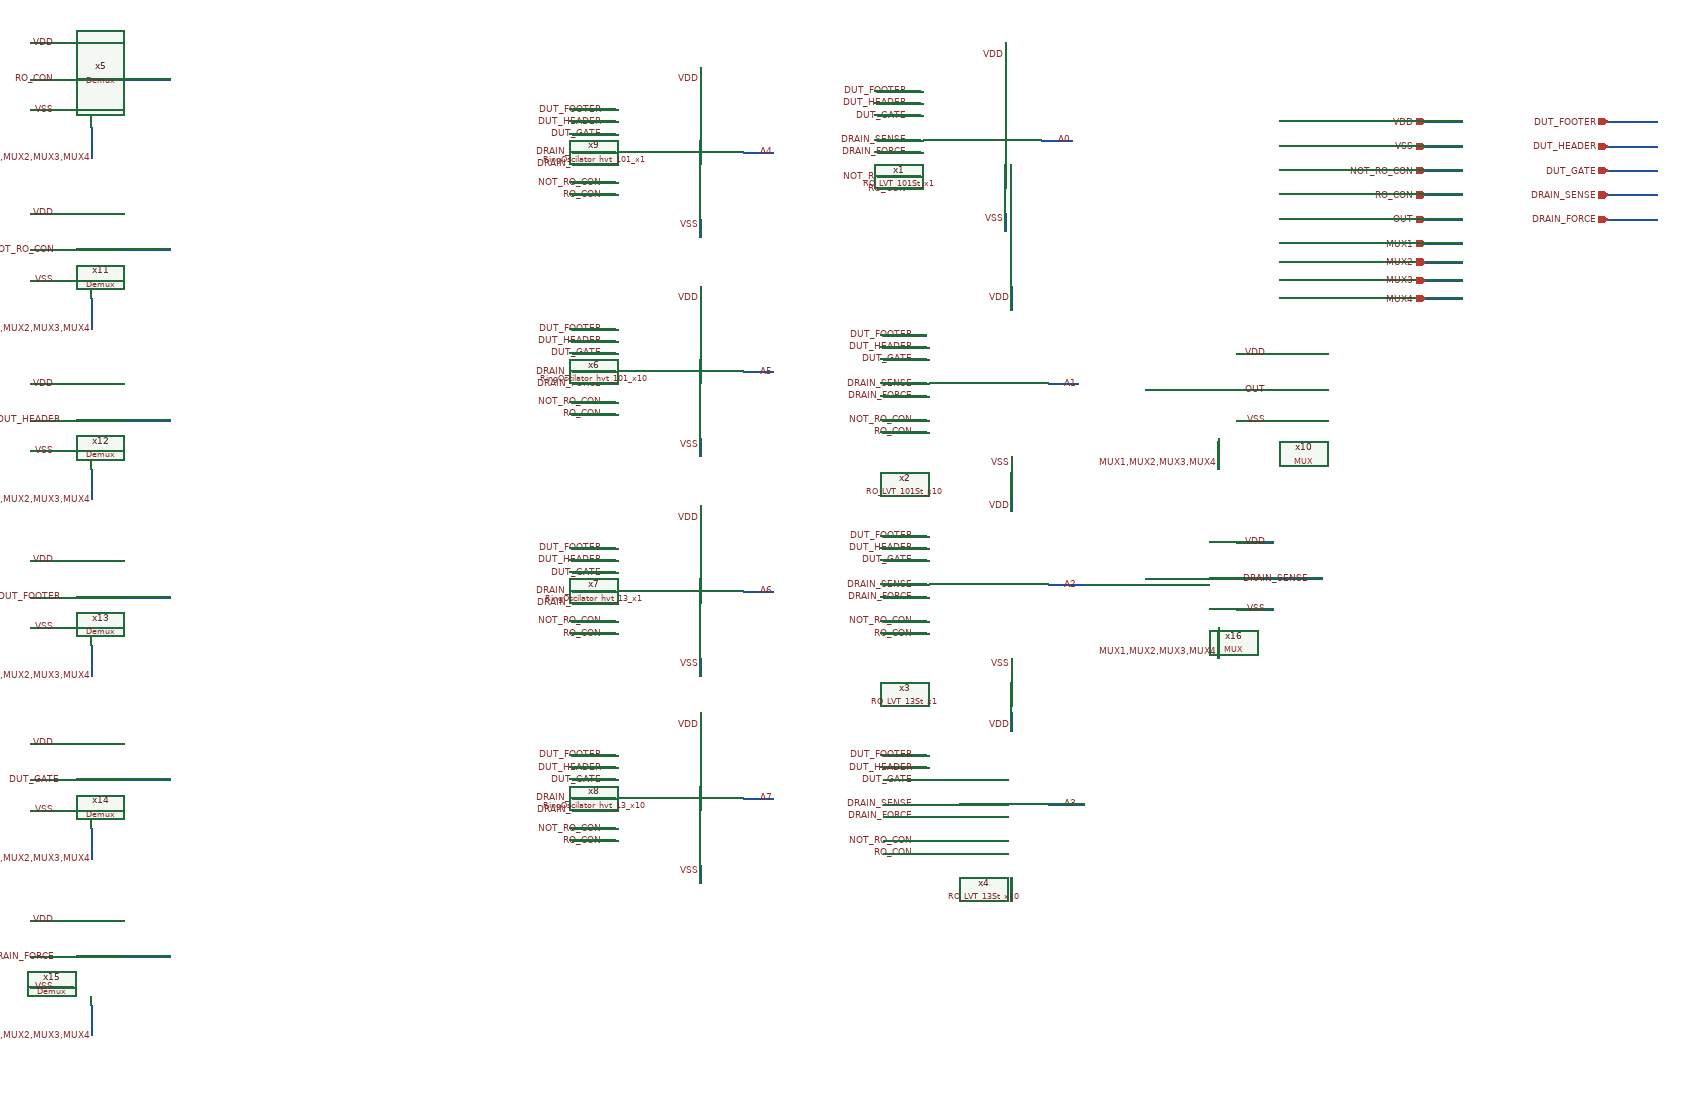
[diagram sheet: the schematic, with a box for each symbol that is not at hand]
v {xschem version=3.4.6RC file_version=1.2
}
G {}
K {}
V {}
S {}
E {}
N 210 -40 210 0 {
lab=VDD}
N 0 40 70 40 {
lab=DUT_FOOTER}
N 0 60 70 60 {
lab=DUT_HEADER}
N -0 80 70 80 {
lab=DUT_GATE}
N 0 120 70 120 {
lab=DRAIN_SENSE}
N 0 140 70 140 {
lab=DRAIN_FORCE}
N 0 180 70 180 {
lab=NOT_RO_CON}
N 0 200 70 200 {
lab=RO_CON}
N 270 120 320 120 {
lab=A1}
N 210 240 210 270 {
lab=VSS}
N 210 300 210 330 {
lab=VDD}
N 0 370 70 370 {
lab=DUT_FOOTER}
N 0 390 70 390 {
lab=DUT_HEADER}
N -0 410 70 410 {
lab=DUT_GATE}
N 0 450 70 450 {
lab=DRAIN_SENSE}
N -0 470 70 470 {
lab=DRAIN_FORCE}
N -0 510 70 510 {
lab=NOT_RO_CON}
N -0 530 70 530 {
lab=RO_CON}
N 210 570 210 610 {
lab=VSS}
N 270 450 330 450 {
lab=A2}
N 890 -310 950 -310 {
lab=VDD}
N 890 -270 950 -270 {
lab=VSS}
N 890 -230 950 -230 {
lab=NOT_RO_CON}
N 890 -190 950 -190 {
lab=RO_CON}
N 1190 -310 1270 -310 {
lab=DUT_FOOTER}
N 1190 -270 1270 -270 {
lab=DUT_HEADER}
N 1190 -230 1270 -230 {
lab=DUT_GATE}
N 1190 -190 1270 -190 {
lab=DRAIN_SENSE}
N 1190 -150 1270 -150 {
lab=DRAIN_FORCE}
N 890 -150 950 -150 {
lab=OUT}
N 890 -110 950 -110 {
lab=MUX1}
N 210 660 210 690 {
lab=VDD}
N 0 730 70 730 {
lab=DUT_FOOTER}
N 0 750 70 750 {
lab=DUT_HEADER}
N 0 770 70 770 {
lab=DUT_GATE}
N 0 810 70 810 {
lab=DRAIN_SENSE}
N 0 830 70 830 {
lab=DRAIN_FORCE}
N 0 870 70 870 {
lab=NOT_RO_CON}
N 0 890 70 890 {
lab=RO_CON}
N 210 930 210 970 {
lab=VSS}
N 270 810 330 810 {
lab=A3}
N 200 -440 200 -400 {
lab=VDD}
N -10 -360 60 -360 {
lab=DUT_FOOTER}
N -10 -340 60 -340 {
lab=DUT_HEADER}
N -10 -320 60 -320 {
lab=DUT_GATE}
N -10 -280 60 -280 {
lab=DRAIN_SENSE}
N -10 -260 60 -260 {
lab=DRAIN_FORCE}
N -10 -220 60 -220 {
lab=NOT_RO_CON}
N -10 -200 60 -200 {
lab=RO_CON}
N 260 -280 310 -280 {
lab=A0}
N 200 -160 200 -130 {
lab=VSS}
N -300 -400 -300 -360 {
lab=VDD}
N -510 -330 -440 -330 {
lab=DUT_FOOTER}
N -510 -310 -440 -310 {
lab=DUT_HEADER}
N -510 -290 -440 -290 {
lab=DUT_GATE}
N -510 -260 -440 -260 {
lab=DRAIN_SENSE}
N -510 -240 -440 -240 {
lab=DRAIN_FORCE}
N -510 -210 -440 -210 {
lab=NOT_RO_CON}
N -510 -190 -440 -190 {
lab=RO_CON}
N -230 -260 -180 -260 {
lab=A4}
N -300 -150 -300 -120 {
lab=VSS}
N -300 -40 -300 0 {
lab=VDD}
N -510 30 -440 30 {
lab=DUT_FOOTER}
N -510 50 -440 50 {
lab=DUT_HEADER}
N -510 70 -440 70 {
lab=DUT_GATE}
N -510 100 -440 100 {
lab=DRAIN_SENSE}
N -510 120 -440 120 {
lab=DRAIN_FORCE}
N -510 150 -440 150 {
lab=NOT_RO_CON}
N -510 170 -440 170 {
lab=RO_CON}
N -230 100 -180 100 {
lab=A5}
N -300 210 -300 240 {
lab=VSS}
N -300 320 -300 360 {
lab=VDD}
N -510 390 -440 390 {
lab=DUT_FOOTER}
N -510 410 -440 410 {
lab=DUT_HEADER}
N -510 430 -440 430 {
lab=DUT_GATE}
N -510 460 -440 460 {
lab=DRAIN_SENSE}
N -510 480 -440 480 {
lab=DRAIN_FORCE}
N -510 510 -440 510 {
lab=NOT_RO_CON}
N -510 530 -440 530 {
lab=RO_CON}
N -230 460 -180 460 {
lab=A6}
N -300 570 -300 600 {
lab=VSS}
N -300 660 -300 700 {
lab=VDD}
N -510 730 -440 730 {
lab=DUT_FOOTER}
N -510 750 -440 750 {
lab=DUT_HEADER}
N -510 770 -440 770 {
lab=DUT_GATE}
N -510 800 -440 800 {
lab=DRAIN_SENSE}
N -510 820 -440 820 {
lab=DRAIN_FORCE}
N -510 850 -440 850 {
lab=NOT_RO_CON}
N -510 870 -440 870 {
lab=RO_CON}
N -230 800 -180 800 {
lab=A7}
N -300 910 -300 940 {
lab=VSS}
N 580 70 640 70 {
lab=VDD}
N 580 130 640 130 {
lab=OUT}
N 580 180 640 180 {
lab=VSS}
N 550 210 550 260 {
lab=#net1}
N 430 130 510 130 {
lab=#net2}
N -1400 -380 -1330 -380 {
lab=RO_CON}
N -1400 -330 -1330 -330 {
lab=VSS}
N -1400 -440 -1330 -440 {
lab=VDD}
N -1300 -300 -1300 -250 {
lab=MUX1,MUX2,MUX3,MUX4}
N -1260 -380 -1170 -380 {
lab=#net3}
N -1400 -100 -1330 -100 {
lab=NOT_RO_CON}
N -1400 -50 -1330 -50 {
lab=VSS}
N -1400 -160 -1330 -160 {
lab=VDD}
N -1300 -20 -1300 30 {
lab=MUX1,MUX2,MUX3,MUX4}
N -1260 -100 -1170 -100 {
lab=#net4}
N -1400 180 -1330 180 {
lab=DUT_HEADER}
N -1400 230 -1330 230 {
lab=VSS}
N -1400 120 -1330 120 {
lab=VDD}
N -1300 260 -1300 310 {
lab=MUX1,MUX2,MUX3,MUX4}
N -1260 180 -1170 180 {
lab=#net5}
N -1400 470 -1330 470 {
lab=DUT_FOOTER}
N -1400 520 -1330 520 {
lab=VSS}
N -1400 410 -1330 410 {
lab=VDD}
N -1300 550 -1300 600 {
lab=MUX1,MUX2,MUX3,MUX4}
N -1260 470 -1170 470 {
lab=#net6}
N -1400 770 -1330 770 {
lab=DUT_GATE}
N -1400 820 -1330 820 {
lab=VSS}
N -1400 710 -1330 710 {
lab=VDD}
N -1300 850 -1300 900 {
lab=MUX1,MUX2,MUX3,MUX4}
N -1260 770 -1170 770 {
lab=#net7}
N -1400 1060 -1330 1060 {
lab=DRAIN_FORCE}
N -1400 1110 -1330 1110 {
lab=VSS}
N -1400 1000 -1330 1000 {
lab=VDD}
N -1300 1140 -1300 1190 {
lab=MUX1,MUX2,MUX3,MUX4}
N -1260 1060 -1170 1060 {
lab=#net8}
N 890 -80 950 -80 {
lab=MUX2}
N 890 -50 950 -50 {
lab=MUX3}
N 890 -20 950 -20 {
lab=MUX4}
N 580 380 640 380 {
lab=VDD}
N 580 440 640 440 {
lab=DRAIN_SENSE}
N 580 490 640 490 {
lab=VSS}
N 550 520 550 570 {
lab=#net9}
N 430 440 510 440 {
lab=#net10}
N 640 440 720 440 {
lab=DRAIN_SENSE}
C {lab_wire.sym} 210 -20 0 0 {name=p2 sig_type=std_logic lab=VDD}
C {lab_wire.sym} 210 320 0 0 {name=p3 sig_type=std_logic lab=VDD}
C {lab_wire.sym} 210 580 2 1 {name=p4 sig_type=std_logic lab=VSS}
C {lab_wire.sym} 210 250 2 1 {name=p5 sig_type=std_logic lab=VSS}
C {lab_wire.sym} 50 60 0 0 {name=p14 sig_type=std_logic lab=DUT_HEADER}
C {lab_wire.sym} 50 40 0 0 {name=p15 sig_type=std_logic lab=DUT_FOOTER}
C {lab_wire.sym} 50 80 0 0 {name=p16 sig_type=std_logic lab=DUT_GATE}
C {lab_wire.sym} 50 120 0 0 {name=p17 sig_type=std_logic lab=DRAIN_SENSE}
C {lab_wire.sym} 50 140 0 0 {name=p18 sig_type=std_logic lab=DRAIN_FORCE}
C {lab_wire.sym} 50 180 0 0 {name=p19 sig_type=std_logic lab=NOT_RO_CON}
C {lab_wire.sym} 50 200 0 0 {name=p20 sig_type=std_logic lab=RO_CON}
C {lab_wire.sym} 50 390 0 0 {name=p21 sig_type=std_logic lab=DUT_HEADER}
C {lab_wire.sym} 50 370 0 0 {name=p22 sig_type=std_logic lab=DUT_FOOTER}
C {lab_wire.sym} 50 410 0 0 {name=p23 sig_type=std_logic lab=DUT_GATE}
C {lab_wire.sym} 50 450 0 0 {name=p24 sig_type=std_logic lab=DRAIN_SENSE}
C {lab_wire.sym} 50 470 0 0 {name=p25 sig_type=std_logic lab=DRAIN_FORCE}
C {lab_wire.sym} 50 510 0 0 {name=p26 sig_type=std_logic lab=NOT_RO_CON}
C {lab_wire.sym} 50 530 0 0 {name=p27 sig_type=std_logic lab=RO_CON}
C {lab_wire.sym} 320 120 0 0 {name=p29 sig_type=std_logic lab=A1}
C {lab_wire.sym} 320 450 0 0 {name=p30 sig_type=std_logic lab=A2}
C {iopin.sym} 890 -310 2 0 {name=p81 lab=VDD}
C {iopin.sym} 890 -270 2 0 {name=p82 lab=VSS}
C {iopin.sym} 890 -230 2 0 {name=p83 lab=NOT_RO_CON}
C {iopin.sym} 890 -190 2 0 {name=p84 lab=RO_CON}
C {iopin.sym} 1190 -310 2 0 {name=p85 lab=DUT_FOOTER}
C {iopin.sym} 1190 -270 2 0 {name=p86 lab=DUT_HEADER}
C {iopin.sym} 1190 -230 2 0 {name=p87 lab=DUT_GATE}
C {iopin.sym} 1190 -190 2 0 {name=p88 lab=DRAIN_SENSE}
C {iopin.sym} 1190 -150 2 0 {name=p89 lab=DRAIN_FORCE}
C {iopin.sym} 890 -150 2 0 {name=p90 lab=OUT}
C {iopin.sym} 890 -110 2 0 {name=p37 lab=MUX1}
C {/foss/designs/RO_Aging_UNICASS/LVT/RO_LVT_101St_x10/RO_LVT_101St_x10.sym} 70 240 0 0 {name=x2}
C {/foss/designs/RO_Aging_UNICASS/LVT/RO_LVT_13St_x1/RO_LVT_13St_x1.sym} 50 570 0 0 {name=x3}
C {lab_wire.sym} 210 680 0 0 {name=p38 sig_type=std_logic lab=VDD}
C {lab_wire.sym} 210 940 2 1 {name=p39 sig_type=std_logic lab=VSS}
C {lab_wire.sym} 50 750 0 0 {name=p40 sig_type=std_logic lab=DUT_HEADER}
C {lab_wire.sym} 50 730 0 0 {name=p41 sig_type=std_logic lab=DUT_FOOTER}
C {lab_wire.sym} 50 770 0 0 {name=p42 sig_type=std_logic lab=DUT_GATE}
C {lab_wire.sym} 50 810 0 0 {name=p43 sig_type=std_logic lab=DRAIN_SENSE}
C {lab_wire.sym} 50 830 0 0 {name=p44 sig_type=std_logic lab=DRAIN_FORCE}
C {lab_wire.sym} 50 870 0 0 {name=p45 sig_type=std_logic lab=NOT_RO_CON}
C {lab_wire.sym} 50 890 0 0 {name=p46 sig_type=std_logic lab=RO_CON}
C {lab_wire.sym} 320 810 0 0 {name=p47 sig_type=std_logic lab=A3}
C {/foss/designs/RO_Aging_UNICASS/LVT/RO_LVT_13St_x10/RO_LVT_13St_x10.sym} 50 930 0 0 {name=x4}
C {lab_wire.sym} 200 -420 0 0 {name=p1 sig_type=std_logic lab=VDD}
C {lab_wire.sym} 200 -150 2 1 {name=p6 sig_type=std_logic lab=VSS}
C {lab_wire.sym} 40 -340 0 0 {name=p7 sig_type=std_logic lab=DUT_HEADER}
C {lab_wire.sym} 40 -360 0 0 {name=p8 sig_type=std_logic lab=DUT_FOOTER}
C {lab_wire.sym} 40 -320 0 0 {name=p9 sig_type=std_logic lab=DUT_GATE}
C {lab_wire.sym} 40 -280 0 0 {name=p10 sig_type=std_logic lab=DRAIN_SENSE}
C {lab_wire.sym} 40 -260 0 0 {name=p11 sig_type=std_logic lab=DRAIN_FORCE}
C {lab_wire.sym} 40 -220 0 0 {name=p12 sig_type=std_logic lab=NOT_RO_CON}
C {lab_wire.sym} 40 -200 0 0 {name=p13 sig_type=std_logic lab=RO_CON}
C {lab_wire.sym} 310 -280 0 0 {name=p48 sig_type=std_logic lab=A0}
C {/foss/designs/RO_Aging_UNICASS/LVT/RO_LVT_101St_x1/RO_LVT_101St_x1.sym} 60 -160 0 0 {name=x1}
C {lab_wire.sym} -300 -380 0 0 {name=p78 sig_type=std_logic lab=VDD}
C {lab_wire.sym} -300 -140 2 1 {name=p79 sig_type=std_logic lab=VSS}
C {lab_wire.sym} -460 -310 0 0 {name=p80 sig_type=std_logic lab=DUT_HEADER}
C {lab_wire.sym} -460 -330 0 0 {name=p91 sig_type=std_logic lab=DUT_FOOTER}
C {lab_wire.sym} -460 -290 0 0 {name=p92 sig_type=std_logic lab=DUT_GATE}
C {lab_wire.sym} -460 -260 0 0 {name=p93 sig_type=std_logic lab=DRAIN_SENSE}
C {lab_wire.sym} -460 -240 0 0 {name=p94 sig_type=std_logic lab=DRAIN_FORCE}
C {lab_wire.sym} -460 -210 0 0 {name=p95 sig_type=std_logic lab=NOT_RO_CON}
C {lab_wire.sym} -460 -190 0 0 {name=p96 sig_type=std_logic lab=RO_CON}
C {lab_wire.sym} -180 -260 0 0 {name=p97 sig_type=std_logic lab=A4}
C {/foss/designs/RO_Aging_UNICASS/HVT/RingOscilator_hvt_101_x1/RingOscilator_hvt_101_x1.sym} -330 -260 0 0 {name=x9}
C {lab_wire.sym} -300 -20 0 0 {name=p28 sig_type=std_logic lab=VDD}
C {lab_wire.sym} -300 220 2 1 {name=p49 sig_type=std_logic lab=VSS}
C {lab_wire.sym} -460 50 0 0 {name=p50 sig_type=std_logic lab=DUT_HEADER}
C {lab_wire.sym} -460 30 0 0 {name=p51 sig_type=std_logic lab=DUT_FOOTER}
C {lab_wire.sym} -460 70 0 0 {name=p52 sig_type=std_logic lab=DUT_GATE}
C {lab_wire.sym} -460 100 0 0 {name=p53 sig_type=std_logic lab=DRAIN_SENSE}
C {lab_wire.sym} -460 120 0 0 {name=p54 sig_type=std_logic lab=DRAIN_FORCE}
C {lab_wire.sym} -460 150 0 0 {name=p55 sig_type=std_logic lab=NOT_RO_CON}
C {lab_wire.sym} -460 170 0 0 {name=p56 sig_type=std_logic lab=RO_CON}
C {lab_wire.sym} -180 100 0 0 {name=p57 sig_type=std_logic lab=A5}
C {lab_wire.sym} -300 340 0 0 {name=p58 sig_type=std_logic lab=VDD}
C {lab_wire.sym} -300 580 2 1 {name=p59 sig_type=std_logic lab=VSS}
C {lab_wire.sym} -460 410 0 0 {name=p60 sig_type=std_logic lab=DUT_HEADER}
C {lab_wire.sym} -460 390 0 0 {name=p61 sig_type=std_logic lab=DUT_FOOTER}
C {lab_wire.sym} -460 430 0 0 {name=p62 sig_type=std_logic lab=DUT_GATE}
C {lab_wire.sym} -460 460 0 0 {name=p63 sig_type=std_logic lab=DRAIN_SENSE}
C {lab_wire.sym} -460 480 0 0 {name=p64 sig_type=std_logic lab=DRAIN_FORCE}
C {lab_wire.sym} -460 510 0 0 {name=p65 sig_type=std_logic lab=NOT_RO_CON}
C {lab_wire.sym} -460 530 0 0 {name=p66 sig_type=std_logic lab=RO_CON}
C {lab_wire.sym} -180 460 0 0 {name=p67 sig_type=std_logic lab=A6}
C {lab_wire.sym} -300 680 0 0 {name=p68 sig_type=std_logic lab=VDD}
C {lab_wire.sym} -300 920 2 1 {name=p69 sig_type=std_logic lab=VSS}
C {lab_wire.sym} -460 750 0 0 {name=p70 sig_type=std_logic lab=DUT_HEADER}
C {lab_wire.sym} -460 730 0 0 {name=p71 sig_type=std_logic lab=DUT_FOOTER}
C {lab_wire.sym} -460 770 0 0 {name=p72 sig_type=std_logic lab=DUT_GATE}
C {lab_wire.sym} -460 800 0 0 {name=p73 sig_type=std_logic lab=DRAIN_SENSE}
C {lab_wire.sym} -460 820 0 0 {name=p74 sig_type=std_logic lab=DRAIN_FORCE}
C {lab_wire.sym} -460 850 0 0 {name=p75 sig_type=std_logic lab=NOT_RO_CON}
C {lab_wire.sym} -460 870 0 0 {name=p76 sig_type=std_logic lab=RO_CON}
C {lab_wire.sym} -180 800 0 0 {name=p77 sig_type=std_logic lab=A7}
C {/foss/designs/RO_Aging_UNICASS/HVT/RingOscilator_hvt_101_x10/RingOscilator_hvt_101_x10.sym} -330 100 0 0 {name=x6}
C {/foss/designs/RO_Aging_UNICASS/HVT/RingOscilator_hvt_13_x1/RingOscilator_hvt_13_x1.sym} -330 460 0 0 {name=x7}
C {/foss/designs/RO_Aging_UNICASS/HVT/RingOscilator_hvt_13_x10/RingOscilator_hvt_13_x10.sym} -330 800 0 0 {name=x8}
C {/foss/designs/RO_Aging_UNICASS/MUX/MUX.sym} 530 120 0 0 {name=x10}
C {lab_wire.sym} 630 70 0 0 {name=p31 sig_type=std_logic lab=VDD}
C {lab_wire.sym} 630 180 2 1 {name=p32 sig_type=std_logic lab=VSS}
C {lab_wire.sym} 630 130 0 0 {name=p33 sig_type=std_logic lab=OUT}
C {/foss/designs/RO_Aging_UNICASS/MUX/Demux.sym} -1300 -220 0 0 {name=x5}
C {lab_wire.sym} -1360 -440 0 0 {name=p34 sig_type=std_logic lab=VDD}
C {lab_wire.sym} -1360 -330 0 0 {name=p35 sig_type=std_logic lab=VSS}
C {lab_wire.sym} -1360 -380 0 0 {name=p36 sig_type=std_logic lab=RO_CON}
C {lab_wire.sym} -1300 -250 0 0 {name=p98 sig_type=std_logic lab=MUX1,MUX2,MUX3,MUX4}
C {/foss/designs/RO_Aging_UNICASS/MUX/Demux.sym} -1300 60 0 0 {name=x11}
C {lab_wire.sym} -1360 -160 0 0 {name=p99 sig_type=std_logic lab=VDD}
C {lab_wire.sym} -1360 -50 0 0 {name=p100 sig_type=std_logic lab=VSS}
C {lab_wire.sym} -1360 -100 0 0 {name=p101 sig_type=std_logic lab=NOT_RO_CON}
C {lab_wire.sym} -1300 30 0 0 {name=p102 sig_type=std_logic lab=MUX1,MUX2,MUX3,MUX4}
C {/foss/designs/RO_Aging_UNICASS/MUX/Demux.sym} -1300 340 0 0 {name=x12}
C {lab_wire.sym} -1360 120 0 0 {name=p103 sig_type=std_logic lab=VDD}
C {lab_wire.sym} -1360 230 0 0 {name=p104 sig_type=std_logic lab=VSS}
C {lab_wire.sym} -1300 310 0 0 {name=p106 sig_type=std_logic lab=MUX1,MUX2,MUX3,MUX4}
C {/foss/designs/RO_Aging_UNICASS/MUX/Demux.sym} -1300 630 0 0 {name=x13}
C {lab_wire.sym} -1360 410 0 0 {name=p107 sig_type=std_logic lab=VDD}
C {lab_wire.sym} -1360 520 0 0 {name=p108 sig_type=std_logic lab=VSS}
C {lab_wire.sym} -1300 600 0 0 {name=p110 sig_type=std_logic lab=MUX1,MUX2,MUX3,MUX4}
C {/foss/designs/RO_Aging_UNICASS/MUX/Demux.sym} -1300 930 0 0 {name=x14}
C {lab_wire.sym} -1360 710 0 0 {name=p111 sig_type=std_logic lab=VDD}
C {lab_wire.sym} -1360 820 0 0 {name=p112 sig_type=std_logic lab=VSS}
C {lab_wire.sym} -1300 900 0 0 {name=p114 sig_type=std_logic lab=MUX1,MUX2,MUX3,MUX4}
C {/foss/designs/RO_Aging_UNICASS/MUX/Demux.sym} -1300 1220 0 0 {name=x15}
C {lab_wire.sym} -1360 1000 0 0 {name=p115 sig_type=std_logic lab=VDD}
C {lab_wire.sym} -1360 1110 0 0 {name=p116 sig_type=std_logic lab=VSS}
C {lab_wire.sym} -1300 1190 0 0 {name=p118 sig_type=std_logic lab=MUX1,MUX2,MUX3,MUX4}
C {lab_wire.sym} -1350 180 0 0 {name=p105 sig_type=std_logic lab=DUT_HEADER}
C {lab_wire.sym} -1350 470 0 0 {name=p109 sig_type=std_logic lab=DUT_FOOTER}
C {lab_wire.sym} -1350 770 0 0 {name=p113 sig_type=std_logic lab=DUT_GATE}
C {lab_wire.sym} -1360 1060 0 0 {name=p117 sig_type=std_logic lab=DRAIN_FORCE}
C {iopin.sym} 890 -80 2 0 {name=p119 lab=MUX2}
C {iopin.sym} 890 -50 2 0 {name=p120 lab=MUX3}
C {iopin.sym} 890 -20 2 0 {name=p121 lab=MUX4}
C {/foss/designs/RO_Aging_UNICASS/MUX/MUX.sym} 530 430 0 0 {name=x16}
C {lab_wire.sym} 630 380 0 0 {name=p122 sig_type=std_logic lab=VDD}
C {lab_wire.sym} 630 490 2 1 {name=p123 sig_type=std_logic lab=VSS}
C {lab_wire.sym} 700 440 0 0 {name=p124 sig_type=std_logic lab=DRAIN_SENSE}
C {lab_wire.sym} 550 250 0 0 {name=p125 sig_type=std_logic lab=MUX1,MUX2,MUX3,MUX4}
C {lab_wire.sym} 550 560 0 0 {name=p126 sig_type=std_logic lab=MUX1,MUX2,MUX3,MUX4}
